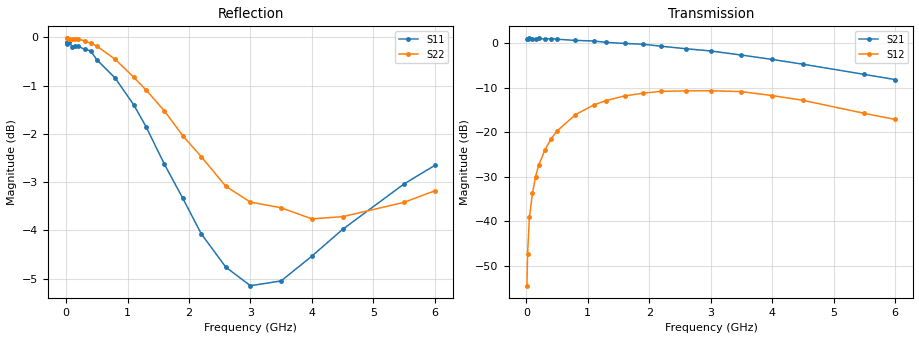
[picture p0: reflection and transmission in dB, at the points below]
! SIEMENS Small Signal Semiconductors
! BFP181
! Si NPN RF Bipolar Junction Transistor in SOT143
! VCE = 0.5 V  IC = 0.3 mA
! Common Emitter S-Parameters:  March  1996
# GHz  S  MA  R  50
!  f  S11  S21  S12  S22
! GHz  MAG  ANG  MAG  ANG  MAG  ANG  MAG  ANG
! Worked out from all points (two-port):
!   36 points, 10 MHz to 6 GHz, reference 50 ohm
!   highest |S21| = 1.09 dB at 50 MHz (marker M1); lowest = -8.2 dB at 6 GHz (marker M2)
!   |S21| within 3 dB of the highest: start of sweep to 3.095 GHz
!   lowest |S11| = -5.1 dB at 3 GHz (marker M3), VSWR 3.47, Z = 14.4 - j1.92 ohm
!   |S11| at or under -10 dB: nowhere
!   |S22| runs from -3.8 to 0.0 dB; largest |S21 - S12| = 1.1
!   S11 on the Smith chart (normalised r, x): 10 MHz: 64, -66; 800 MHz: 0.34, -2.43; 1.6 GHz: 0.30, -0.98; 2.6 GHz: 0.28, -0.24; 4 GHz: 0.30, +0.38; 6 GHz: 0.32, +1.03
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0.01  0.985 -0.9  1.108 179.8  0.0019 88.6  0.9978 -0.3
0.02  0.9898 -1.1  1.123 179.6  0.0043 91.1  0.9978 -0.6
0.05  0.9888 -2.6  1.134 177.1  0.0111 90.2  0.9971 -1.5
0.1  0.9784 -5.6  1.107 174.1  0.0208 84.7  0.9969 -3.0
0.15  0.9796 -8.3  1.117 171.1  0.0318 83.0  0.9968 -4.5
0.2  0.9787 -11.2  1.131 167.8  0.0425 81.6  0.9965 -6.0
0.3  0.9722 -16.6  1.113 162.6  0.063 77.0  0.9915 -9.1
0.4  0.9682 -22.2  1.125 155.8  0.084 73.1  0.9865 -12.1
0.5  0.9481 -28.0  1.109 149.6  0.1036 68.6  0.9797 -15.1
0.8  0.9074 -44.0  1.076 132.8  0.1579 56.3  0.949 -23.8
1.1  0.8515 -61.0  1.059 116.4  0.2031 44.7  0.9095 -31.8
1.3  0.8084 -71.9  1.023 106.4  0.2275 37.0  0.8823 -37.0
1.6  0.7389 -88.4  0.994 91.5  0.2561 27.4  0.8393 -43.5
1.9  0.681 -107.5  0.975 77.3  0.2751 17.5  0.7907 -49.8
2.2  0.6258 -125.1  0.925 63.6  0.2883 9.0  0.7524 -55.4
2.6  0.5779 -150.6  0.867 47.8  0.2919 -1.4  0.7009 -62.3
3  0.5529 -175.2  0.819 32.1  0.2928 -12.1  0.675 -69.3
3.5  0.5592 157.0  0.737 15.0  0.2866 -22.8  0.6659 -77.8
4  0.5933 135.3  0.658 0.2  0.2585 -32.8  0.6485 -88.2
4.5  0.6324 117.7  0.582 -12.4  0.2288 -41.9  0.6519 -99.7
5.5  0.7048 94.6  0.447 -31.0  0.1634 -48.8  0.6746 -122.8
6  0.7367 85.7  0.391 -38.0  0.1397 -47.1  0.6934 -134.6
